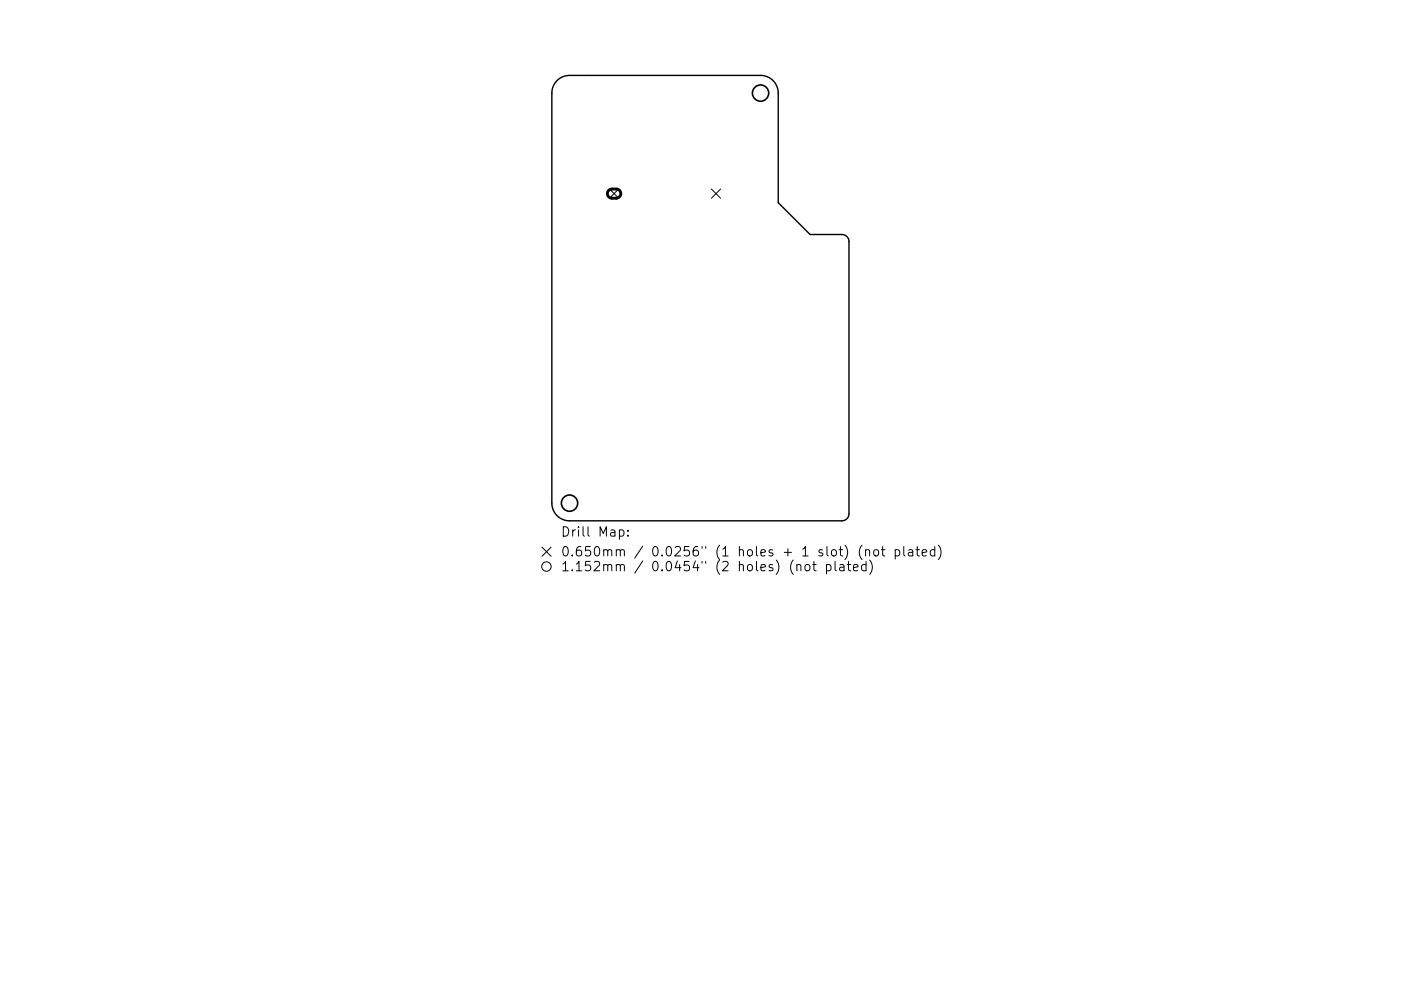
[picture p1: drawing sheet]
<svg xmlns="http://www.w3.org/2000/svg" width="297mm" height="210mm" viewBox="0 0 297 210" stroke-linecap="round" stroke-linejoin="round" font-family="sans-serif">
<defs><g id="words">
<g font-size="2.8">
<text x="118.9" y="113.9">Drill Map:</text>
<text x="118.9" y="118.1">0.650mm / 0.0256&quot; (1 holes + 1 slot) (not plated)</text>
<text x="118.9" y="121.2">1.152mm / 0.0454&quot; (2 holes) (not plated)</text>
</g>
</g></defs>
<path d="M118.1 17.1a3.8 3.8 0 0 1 2.7-1.1h40.5a3.8 3.8 0 0 1 3.7 3.8v23.2l6.8 6.8h6.7a1.5 1.5 0 0 1 1.5 1.5v57.7a1.5 1.5 0 0 1-1.5 1.5h-57.7a3.8 3.8 0 0 1-3.8-3.7v-87a3.8 3.8 0 0 1 1.1-2.7z" fill="none" stroke="#000" stroke-width=".3"/>
<g fill="none" stroke="#000" stroke-width=".21">
<path d="M129.2 40.1l2 2M131.2 40.1l-2 2M150.8 40.1l2 2M152.8 40.1l-2 2M114.9 116.1l2 1.9M116.9 116.1l-2 1.9M131.3 112.5l.6-.1 .4 .4v.6l-.2 .3h-.8M133.1 113.6v.2M133.1 112.5v.2M169 120a.5 .5 0 0 1 .8 .1v1M170.8 120a.54 .54 0 0 1 .5-.2 .54 .54 0 0 1 .4 .4v.5a.54 .54 0 0 1-.5 .4 .54 .54 0 0 1-.5-.4zM172.3 119.8h.7"/>
<path d="M172.6 119.1v1.7l.1 .2 .3 .1M175.2 119.9l.6-.1 .4 .4v.5l-.2 .3h-.8M175.2 119.8v2M177 119.1v1.7l.3 .3M178.1 119.9h.8l.1 1.2M179.1 115.7a2.29 2.29 0 0 1 0 3M179.6 119.8h.8M179.9 119.1v1.7l.1 .2 .4 .1M182.8 115.7a2.29 2.29 0 0 0 0 3M183.5 116.8l.3-.2 .5 .1 .1 1.3M183.5 116.6v1.4M183.6 119.9l-.6-.1-.3 .4v.5l.2 .3h.7"/>
<path d="M183.6 119.1v2M184.4 118.8a2.29 2.29 0 0 1 0 3.1M185.3 116.8a.54 .54 0 0 1 .6-.2 .54 .54 0 0 1 .4 .4v.6a.54 .54 0 0 1-.5 .4 .54 .54 0 0 1-.6-.4zM186.9 116.6h.7M187.1 116v1.7l.1 .2 .4 .1M189.8 116.7l.6-.1 .4 .4v.6l-.2 .3h-.8M189.8 116.6v2M191.6 116v1.7l.3 .3M192.7 116.7h.7l.1 1.3M193.5 117.1l-.6 .1a.39 .39 0 0 0-.3 .4 .39 .39 0 0 0 .3 .4l.6-.1M194.2 116.6h.8M194.5 116v1.7l.1 .2 .4 .1"/>
<path d="M195.5 117.3l1-.2-.1-.4-.6-.1-.3 .3 .1 1h.8M198.2 116.7l-.6-.1-.4 .4v.6l.2 .3h.8M198.2 116v2M199 115.7a2.29 2.29 0 0 1 0 3M179 120.2l-.7 .1a.39 .39 0 0 0-.3 .4 .39 .39 0 0 0 .3 .4l.7-.1M181 120.4l.9-.2-.1-.3-.6-.1-.2 .3v.9h.8"/>
<circle cx="115.9" cy="120.2" r="1"/>
</g>
<path d="M129.1 40.4l.5-.3h1.1a.97 .97 0 0 1 .9 1 .97 .97 0 0 1-.9 1h-.9a.97 .97 0 0 1-.9-.6 .97 .97 0 0 1 .2-1.1z" fill="none" stroke="#000" stroke-width=".6"/>
<g fill="none" stroke="#000" stroke-width=".35">
<circle cx="161.3" cy="19.8" r="1.73"/>
<circle cx="120.8" cy="106.8" r="1.73"/>
</g>
<use href="#words"/>
</svg>
